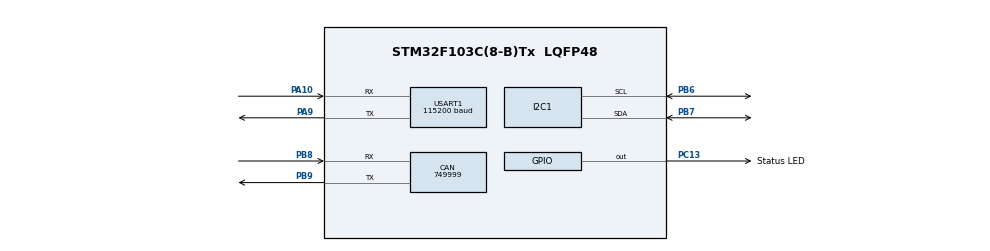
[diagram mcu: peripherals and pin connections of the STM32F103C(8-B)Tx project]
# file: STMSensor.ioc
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CAN.CalculateBaudRate=749999
CAN.CalculateTimeBit=1333
CAN.CalculateTimeQuantum=444.44444444444446
I2C1.I2C_Mode=I2C_Standard
Mcu.Family=STM32F1
Mcu.Name=STM32F103C(8-B)Tx
Mcu.Package=LQFP48
NVIC.PriorityGroup=NVIC_PRIORITYGROUP_4
NVIC.USB_HP_CAN1_TX_IRQn=true\:0\:0\:false\:false\:true\:true\:true\:true
NVIC.USB_LP_CAN1_RX0_IRQn=true\:0\:0\:false\:false\:true\:false\:true\:true
PA10.Mode=Asynchronous
PA10.Signal=USART1_RX
PA9.Mode=Asynchronous
PA9.Signal=USART1_TX
PB6.Mode=I2C
PB6.Signal=I2C1_SCL
PB7.Mode=I2C
PB7.Signal=I2C1_SDA
PB8.Mode=CAN_Activate
PB8.Signal=CAN_RX
PB9.Mode=CAN_Activate
PB9.Signal=CAN_TX
PC13-TAMPER-RTC.GPIO_Label=Status LED
PC13-TAMPER-RTC.GPIO_PuPd=GPIO_PULLUP
PC13-TAMPER-RTC.GPIO_Speed=GPIO_SPEED_FREQ_HIGH
PC13-TAMPER-RTC.Signal=GPIO_Output
PD0-OSC_IN.Mode=HSE-External-Oscillator
PD0-OSC_IN.Signal=RCC_OSC_IN
PD1-OSC_OUT.Mode=HSE-External-Oscillator
PD1-OSC_OUT.Signal=RCC_OSC_OUT
ProjectManager.HeapSize=0x200
ProjectManager.StackSize=0x400
ProjectManager.TargetToolchain=STM32CubeIDE
RCC.AHBFreq_Value=72000000
RCC.APB1CLKDivider=RCC_HCLK_DIV2
RCC.APB1Freq_Value=36000000
RCC.APB1TimFreq_Value=72000000
RCC.APB2Freq_Value=72000000
RCC.APB2TimFreq_Value=72000000
RCC.HCLKFreq_Value=72000000
RCC.PLLMUL=RCC_PLL_MUL9
RCC.PLLSourceVirtual=RCC_PLLSOURCE_HSE
RCC.SYSCLKFreq_VALUE=72000000
RCC.SYSCLKSource=RCC_SYSCLKSOURCE_PLLCLK
RCC.USBFreq_Value=72000000
USART1.BaudRate=115200
USART1.VirtualMode=VM_ASYNC
VP_SYS_VS_ND.Mode=No_Debug
board=custom

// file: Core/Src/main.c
/* USER CODE BEGIN Header */
/**
  ******************************************************************************
  * @file           : main.c
  * @brief          : Main program body
  ******************************************************************************
  * @attention
  *
  * Copyright (c) 2025 STMicroelectronics.
  * All rights reserved.
  *
  * This software is licensed under terms that can be found in the LICENSE file
  * in the root directory of this software component.
  * If no LICENSE file comes with this software, it is provided AS-IS.
  *
  ******************************************************************************
  */
/* USER CODE END Header */
#include "main.h"

/* USER CODE BEGIN Includes */
#include "can.h"
#include "uart.h"
#include "message_handler.h"
#include "vl53l0x.h"
#include "gpio.h"
#include "stdbool.h"

/* USER CODE END Includes */

CAN_HandleTypeDef hcan;

I2C_HandleTypeDef hi2c1;

UART_HandleTypeDef huart1;

/* USER CODE BEGIN PV */
/* Error tracking - using simple flags for each system */
static uint8_t initError = 0;      // Set to 1 if initial sensor setup fails
static uint8_t sensorOK = 0;       // Sensor working flag (0 = error, 1 = working)
static uint8_t reconnectTimer = 0; // Timer for reconnection attempts (counts loops)

/* USER CODE END PV */

void SystemClock_Config(void);
static void MX_GPIO_Init(void);
static void MX_I2C1_Init(void);
static void MX_CAN_Init(void);
static void MX_USART1_UART_Init(void);

int main(void)
{

  /* MCU Configuration--------------------------------------------------------*/

  /* Reset of all peripherals, Initializes the Flash interface and the Systick. */
  HAL_Init();

  /* Configure the system clock */
  SystemClock_Config();

  /* Initialize all configured peripherals */
  MX_GPIO_Init();
  MX_I2C1_Init();
  MX_CAN_Init();
  MX_USART1_UART_Init();
  /* USER CODE BEGIN 2 */
  //CAN_ControllerInit(&hcan);

  /* Attempt to initialize the VL53L0X sensor on I2C bus 1
  * This checks if sensor is connected and responding with correct ID (0xEE) */
  if (VL53L0X_Init(&hi2c1) == HAL_OK) {
	 /* Sensor found and initialized successfully */
	 SendMessage("VL53L0X Sensor Initialize Success...\n\0");
	 sensorOK = 1; // Sensor is detected online.
  } else {
	 /* Sensor initialization failed - either not connected, wrong wiring,
	  * or not a VL53L0X sensor (wrong ID) */
	 SendMessage("VL53L0X Sensor Initialize Fail...\n\0");
	 initError = 1;  // Set error flag to track initialization failure
  }
  /* USER CODE END 2 */

  /* Infinite loop */
  /* USER CODE BEGIN WHILE */
  while (1)
  {
	  /* Check initial sensor state from initialization */
	  if (initError) {
	     sensorOK = 0;  // Sensor failed during init
	  }

	  /* Attempt sensor reconnection every ~1 second if it's not working */
	  if (!sensorOK) {
	     reconnectTimer++;
	     if (reconnectTimer >= 50) {  // 50 loops * 20ms = 1 second
	         reconnectTimer = 0; // Reset reconnectTimer

	         /* Reset I2C bus before trying to reconnect
	                  * This clears any stuck I2C conditions */
	                 HAL_I2C_DeInit(&hi2c1);
	                 HAL_Delay(10);
	                 MX_I2C1_Init();  // Reinitialize I2C peripheral
	                 HAL_Delay(10);

	         /* Try to initialize sensor again */
	         if (VL53L0X_Init(&hi2c1) == HAL_OK) {
	             sensorOK = 1;  // Sensor is back online
	             initError = 0;
	             SendMessage("Sensor reconnected\n\0");
	         }
	     }
	  }

	  /* Read and transmit sensor data if sensor is working */
	  if (sensorOK) {
	     uint16_t distance = VL53L0X_ReadDistance(&hi2c1);

	     if (distance != DISTANCE_ERROR) {
	         /* Valid reading - try to send over USB */
	         SendSensor(distance);
	     } else {
	         /* Sensor read failed - mark as not working */
	         sensorOK = 0;
	         SendMessage("Sensor read failed\n\0");
	     }
	  }

	  /* LED Status Indicator (Pull-Up: LOW = ON, HIGH = OFF)
	  * Different patterns for different states:
	  * - All OK: LED ON (solid)
	  * - Any error: LED OFF */
	  if (sensorOK && UARTok() && CANok()) {
	     /* Everything working - LED ON */
	     HAL_GPIO_WritePin(LED_BUILTIN, GPIO_PIN_RESET);
	  } else {
	     /* Something has failed - LED OFF
	      * Could expand this to blink patterns for specific errors */
	     HAL_GPIO_WritePin(LED_BUILTIN, GPIO_PIN_SET);

	     /* Print which system failed for debugging */
	     if (!sensorOK) SendMessage("ERROR: Sensor\n\0");
	     if (!UARTok())    SendMessage("ERROR: Serial UART\n\0");
	     if (!CANok())    SendMessage("ERROR: CAN\n\0");
	  }

	  /* Wait 20ms before next loop iteration
	  * This matches FRC CAN bus update period (50Hz) */
	  HAL_Delay(20);
    /* USER CODE END WHILE */

  }
}

void SystemClock_Config(void)
{
  RCC_OscInitTypeDef RCC_OscInitStruct = {0};
  RCC_ClkInitTypeDef RCC_ClkInitStruct = {0};

  /** Initializes the RCC Oscillators according to the specified parameters
  * in the RCC_OscInitTypeDef structure.
  */
  RCC_OscInitStruct.OscillatorType = RCC_OSCILLATORTYPE_HSE;
  RCC_OscInitStruct.HSEState = RCC_HSE_ON;
  RCC_OscInitStruct.HSEPredivValue = RCC_HSE_PREDIV_DIV1;
  RCC_OscInitStruct.HSIState = RCC_HSI_ON;
  RCC_OscInitStruct.PLL.PLLState = RCC_PLL_ON;
  RCC_OscInitStruct.PLL.PLLSource = RCC_PLLSOURCE_HSE;
  RCC_OscInitStruct.PLL.PLLMUL = RCC_PLL_MUL6;
  if (HAL_RCC_OscConfig(&RCC_OscInitStruct) != HAL_OK)
  {
    Error_Handler();
  }

  /** Initializes the CPU, AHB and APB buses clocks
  */
  RCC_ClkInitStruct.ClockType = RCC_CLOCKTYPE_HCLK|RCC_CLOCKTYPE_SYSCLK
                              |RCC_CLOCKTYPE_PCLK1|RCC_CLOCKTYPE_PCLK2;
  RCC_ClkInitStruct.SYSCLKSource = RCC_SYSCLKSOURCE_PLLCLK;
  RCC_ClkInitStruct.AHBCLKDivider = RCC_SYSCLK_DIV1;
  RCC_ClkInitStruct.APB1CLKDivider = RCC_HCLK_DIV2;
  RCC_ClkInitStruct.APB2CLKDivider = RCC_HCLK_DIV1;

  if (HAL_RCC_ClockConfig(&RCC_ClkInitStruct, FLASH_LATENCY_1) != HAL_OK)
  {
    Error_Handler();
  }
}

static void MX_CAN_Init(void)
{

  hcan.Instance = CAN1;
  hcan.Init.Prescaler = 16;
  hcan.Init.Mode = CAN_MODE_NORMAL;
  hcan.Init.SyncJumpWidth = CAN_SJW_1TQ;
  hcan.Init.TimeSeg1 = CAN_BS1_1TQ;
  hcan.Init.TimeSeg2 = CAN_BS2_1TQ;
  hcan.Init.TimeTriggeredMode = DISABLE;
  hcan.Init.AutoBusOff = DISABLE;
  hcan.Init.AutoWakeUp = DISABLE;
  hcan.Init.AutoRetransmission = DISABLE;
  hcan.Init.ReceiveFifoLocked = DISABLE;
  hcan.Init.TransmitFifoPriority = DISABLE;
  if (HAL_CAN_Init(&hcan) != HAL_OK)
  {
    Error_Handler();
  }

}

static void MX_I2C1_Init(void)
{

  hi2c1.Instance = I2C1;
  hi2c1.Init.ClockSpeed = 100000;
  hi2c1.Init.DutyCycle = I2C_DUTYCYCLE_2;
  hi2c1.Init.OwnAddress1 = 0;
  hi2c1.Init.AddressingMode = I2C_ADDRESSINGMODE_7BIT;
  hi2c1.Init.DualAddressMode = I2C_DUALADDRESS_DISABLE;
  hi2c1.Init.OwnAddress2 = 0;
  hi2c1.Init.GeneralCallMode = I2C_GENERALCALL_DISABLE;
  hi2c1.Init.NoStretchMode = I2C_NOSTRETCH_DISABLE;
  if (HAL_I2C_Init(&hi2c1) != HAL_OK)
  {
    Error_Handler();
  }

}

static void MX_USART1_UART_Init(void)
{

  huart1.Instance = USART1;
  huart1.Init.BaudRate = 115200;
  huart1.Init.WordLength = UART_WORDLENGTH_8B;
  huart1.Init.StopBits = UART_STOPBITS_1;
  huart1.Init.Parity = UART_PARITY_NONE;
  huart1.Init.Mode = UART_MODE_TX_RX;
  huart1.Init.HwFlowCtl = UART_HWCONTROL_NONE;
  huart1.Init.OverSampling = UART_OVERSAMPLING_16;
  if (HAL_UART_Init(&huart1) != HAL_OK)
  {
    Error_Handler();
  }

}

static void MX_GPIO_Init(void)
{
  GPIO_InitTypeDef GPIO_InitStruct = {0};

  /* GPIO Ports Clock Enable */
  __HAL_RCC_GPIOC_CLK_ENABLE();
  __HAL_RCC_GPIOD_CLK_ENABLE();
  __HAL_RCC_GPIOA_CLK_ENABLE();
  __HAL_RCC_GPIOB_CLK_ENABLE();

  /*Configure GPIO pin Output Level */
  HAL_GPIO_WritePin(Status_LED_GPIO_Port, Status_LED_Pin, GPIO_PIN_RESET);

  /*Configure GPIO pin : Status_LED_Pin */
  GPIO_InitStruct.Pin = Status_LED_Pin;
  GPIO_InitStruct.Mode = GPIO_MODE_OUTPUT_PP;
  GPIO_InitStruct.Pull = GPIO_PULLUP;
  GPIO_InitStruct.Speed = GPIO_SPEED_FREQ_HIGH;
  HAL_GPIO_Init(Status_LED_GPIO_Port, &GPIO_InitStruct);

}

void Error_Handler(void)
{
  __disable_irq();
  while (1)
  {
  }
}
